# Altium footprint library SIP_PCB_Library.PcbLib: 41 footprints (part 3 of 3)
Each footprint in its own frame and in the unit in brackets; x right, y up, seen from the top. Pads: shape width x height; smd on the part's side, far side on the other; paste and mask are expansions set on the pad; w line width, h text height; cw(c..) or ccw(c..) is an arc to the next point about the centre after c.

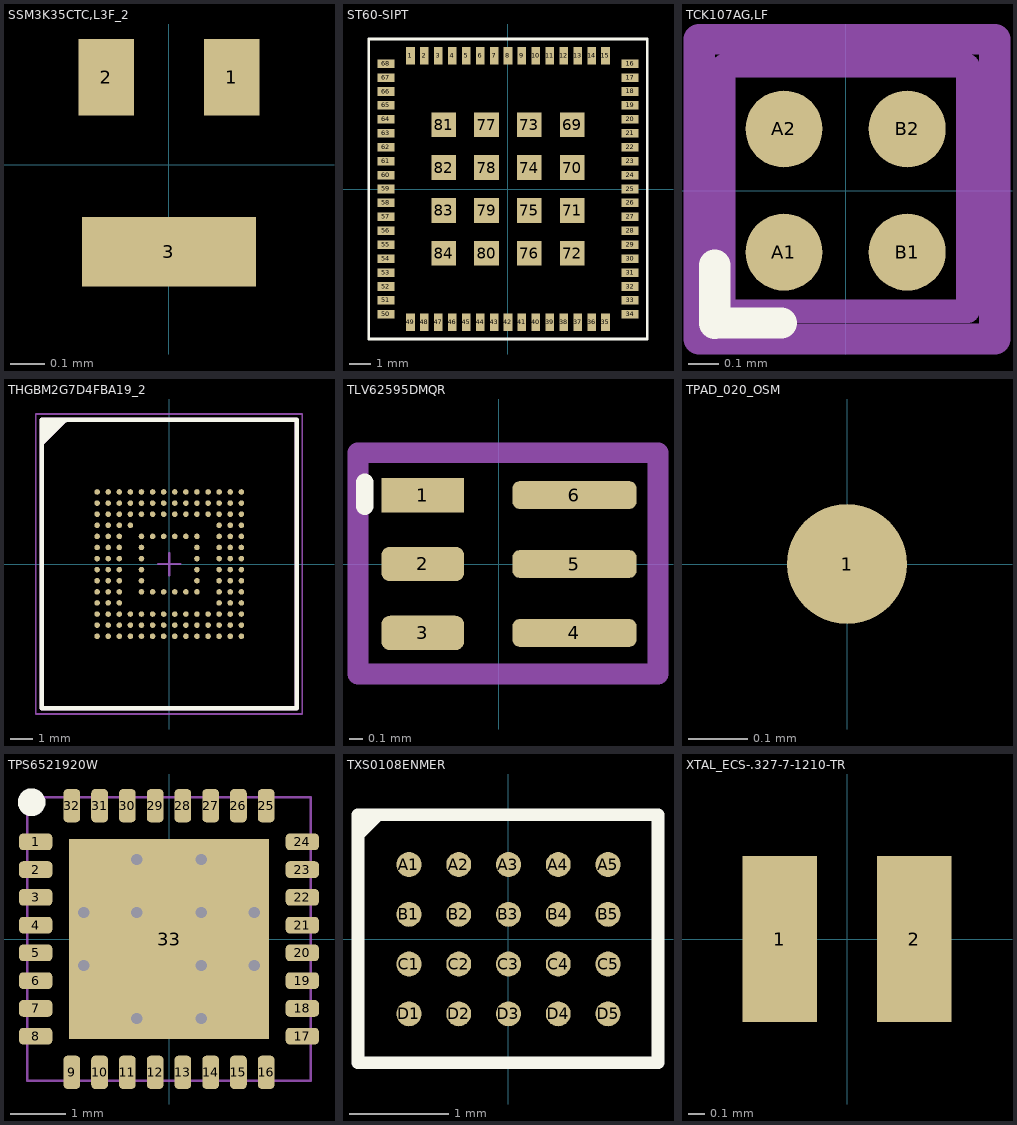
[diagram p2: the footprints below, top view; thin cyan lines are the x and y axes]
## SSM3K35CTC,L3F_2 [mm]
pads (3):
  rect 0.16x0.22 smd: 1(0.18,0.25) 2(-0.18,0.25)
  rect 0.5x0.2 smd: 3(0,-0.25)
3D body "CST3C_z90.stp": height 0.38, standoff 0, extent -0.3,-0.4 0.3,0.4

## ST60-SIPT [mm]
height 0.8
pads (84):
  rect 0.4x0.8 smd mask+0.051: 1(-4.55,6.219) 2(-3.9,6.219) 3(-3.25,6.219) 4(-2.6,6.219) 5(-1.95,6.219) 6(-1.3,6.219) 7(-0.65,6.219) 8(0,6.219) 9(0.65,6.219) 10(1.3,6.219) 11(1.95,6.219) 12(2.6,6.219) 13(3.25,6.219) 14(3.9,6.219) 15(4.55,6.219) 35(4.55,-6.219) 36(3.9,-6.219) 37(3.25,-6.219) 38(2.6,-6.219) 39(1.95,-6.219) 40(1.3,-6.219) 41(0.65,-6.219) 42(0,-6.219) 43(-0.65,-6.219) 44(-1.3,-6.219) 45(-1.95,-6.219) 46(-2.6,-6.219) 47(-3.25,-6.219) 48(-3.9,-6.219) 49(-4.55,-6.219)
  rect 0.8x0.4 smd mask+0.051: 16(5.694,5.85) 17(5.694,5.2) 18(5.694,4.55) 19(5.694,3.9) 20(5.694,3.25) 21(5.694,2.6) 22(5.694,1.95) 23(5.694,1.3) 24(5.694,0.65) 25(5.694,0) 26(5.694,-0.65) 27(5.694,-1.3) 28(5.694,-1.95) 29(5.694,-2.6) 30(5.694,-3.25) 31(5.694,-3.9) 32(5.694,-4.55) 33(5.694,-5.2) 34(5.694,-5.85) 50(-5.694,-5.85) 51(-5.694,-5.2) 52(-5.694,-4.55) 53(-5.694,-3.9) 54(-5.694,-3.25) 55(-5.694,-2.6) 56(-5.694,-1.95) 57(-5.694,-1.3) 58(-5.694,-0.65) 59(-5.694,0) 60(-5.694,0.65) 61(-5.694,1.3) 62(-5.694,1.95) 63(-5.694,2.6) 64(-5.694,3.25) 65(-5.694,3.9) 66(-5.694,4.55) 67(-5.694,5.2) 68(-5.694,5.85)
  rect 1.15x1.15 smd mask+0.051: 69(3,3) 70(3,1) 71(3,-1) 72(3,-3) 73(1,3) 74(1,1) 75(1,-1) 76(1,-3) 77(-1,3) 78(-1,1) 79(-1,-1) 80(-1,-3) 81(-3,3) 82(-3,1) 83(-3,-1) 84(-3,-3)
Top Overlay:
  lines w0.127: -6.5,-7 -6.5,7 6.5,7 6.5,-7 -6.5,-7
Top Courtyard:
  lines w0.025: 6.5,7 6.5,6.987 ; 6.5,6.987 -6.5,6.987 -6.5,-7 6.5,-7 6.5,6.987
3D body "453-00134.STEP": height 1.88, standoff -0.01, extent -6.5,-7 6.5,7

## TCK107AG,LF [mm]
pads (4):
  round 0.25 smd paste-0.03: A1(-0.2,-0.2) A2(-0.2,0.2) B1(0.2,-0.2) B2(0.2,0.2)
Top Overlay:
  lines w0.102: -0.424,-0.243 -0.424,-0.431 -0.209,-0.43
Mechanical 9:
  lines w0.076: -0.395,-0.392 0.396,-0.392 0.396,0.405 -0.395,0.405 -0.395,-0.371 -0.395,-0.392
Top Assembly:
  lines w0.102: -0.475,-0.482 0.484,-0.482 0.484,0.492 -0.475,0.492 -0.475,-0.482
  text "'.Designator'" at 6.86,2.581 h1.78
3D body "TCK107AG,LF.stp": height 0.59, standoff 0, extent -0.395,-0.395 0.395,0.395

## THGBM2G7D4FBA19_2 [mm] "BD584, BGA, 392-Leads, Body 16.0x12.0mm,  Pitch 0.50mm"
height 1.2
pads (153):
  round 0.25 smd: AA1(-3.25,-3.25) AA2(-2.75,-3.25) AA3(-2.25,-3.25) AA4(-1.75,-3.25) AA5(-1.25,-3.25) AA6(-0.75,-3.25) AA7(-0.25,-3.25) AA8(0.25,-3.25) AA9(0.75,-3.25) AA10(1.25,-3.25) AA11(1.75,-3.25) AA12(2.25,-3.25) AA13(2.75,-3.25) AA14(3.25,-3.25) H1(-3.25,3.25) H2(-2.75,3.25) H3(-2.25,3.25) H4(-1.75,3.25) H5(-1.25,3.25) H6(-0.75,3.25) H7(-0.25,3.25) H8(0.25,3.25) H9(0.75,3.25) H10(1.25,3.25) H11(1.75,3.25) H12(2.25,3.25) H13(2.75,3.25) H14(3.25,3.25) J1(-3.25,2.75) J2(-2.75,2.75) J3(-2.25,2.75) J4(-1.75,2.75) J5(-1.25,2.75) J6(-0.75,2.75) J7(-0.25,2.75) J8(0.25,2.75) J9(0.75,2.75) J10(1.25,2.75) J11(1.75,2.75) J12(2.25,2.75) J13(2.75,2.75) J14(3.25,2.75) K1(-3.25,2.25) K2(-2.75,2.25) K3(-2.25,2.25) K4(-1.75,2.25) K5(-1.25,2.25) K6(-0.75,2.25) K7(-0.25,2.25) K8(0.25,2.25) K9(0.75,2.25) K10(1.25,2.25) K11(1.75,2.25) K12(2.25,2.25) K13(2.75,2.25) K14(3.25,2.25) L1(-3.25,1.75) L2(-2.75,1.75) L3(-2.25,1.75) L4(-1.75,1.75) L12(2.25,1.75) L13(2.75,1.75) L14(3.25,1.75) M1(-3.25,1.25) M2(-2.75,1.25) M3(-2.25,1.25) M5(-1.25,1.25) M6(-0.75,1.25) M7(-0.25,1.25) M8(0.25,1.25) M9(0.75,1.25) M10(1.25,1.25) M12(2.25,1.25) M13(2.75,1.25) M14(3.25,1.25) N1(-3.25,0.75) N2(-2.75,0.75) N3(-2.25,0.75) N5(-1.25,0.75) N10(1.25,0.75) N12(2.25,0.75) N13(2.75,0.75) N14(3.25,0.75) P1(-3.25,0.25) P2(-2.75,0.25) P3(-2.25,0.25) P5(-1.25,0.25) P10(1.25,0.25) P12(2.25,0.25) P13(2.75,0.25) P14(3.25,0.25) R1(-3.25,-0.25) R2(-2.75,-0.25) R3(-2.25,-0.25) R5(-1.25,-0.25) R10(1.25,-0.25) R12(2.25,-0.25) R13(2.75,-0.25) R14(3.25,-0.25) T1(-3.25,-0.75) T2(-2.75,-0.75) T3(-2.25,-0.75) T5(-1.25,-0.75) T10(1.25,-0.75) T12(2.25,-0.75) T13(2.75,-0.75) T14(3.25,-0.75) U1(-3.25,-1.25) U2(-2.75,-1.25) U3(-2.25,-1.25) U5(-1.25,-1.25) U6(-0.75,-1.25) U7(-0.25,-1.25) U8(0.25,-1.25) U9(0.75,-1.25) U10(1.25,-1.25) U12(2.25,-1.25) U13(2.75,-1.25) U14(3.25,-1.25) V1(-3.25,-1.75) V2(-2.75,-1.75) V3(-2.25,-1.75) V12(2.25,-1.75) V13(2.75,-1.75) V14(3.25,-1.75) W1(-3.25,-2.25) W2(-2.75,-2.25) W3(-2.25,-2.25) W4(-1.75,-2.25) W5(-1.25,-2.25) W6(-0.75,-2.25) W7(-0.25,-2.25) W8(0.25,-2.25) W9(0.75,-2.25) W10(1.25,-2.25) W11(1.75,-2.25) W12(2.25,-2.25) W13(2.75,-2.25) W14(3.25,-2.25) Y1(-3.25,-2.75) Y2(-2.75,-2.75) Y3(-2.25,-2.75) Y4(-1.75,-2.75) Y5(-1.25,-2.75) Y6(-0.75,-2.75) Y7(-0.25,-2.75) Y8(0.25,-2.75) Y9(0.75,-2.75) Y10(1.25,-2.75) Y11(1.75,-2.75) Y12(2.25,-2.75) Y13(2.75,-2.75) Y14(3.25,-2.75)
Top Overlay:
  circle w0.25: c-5.435,6.17 r0.125
  region: -4.77,6.49 -5.77,5.49 -5.77,6.49
  lines w0.2: -5.715,5.46 -4.715,6.46 ; 5.75,-6.5 5.75,6.5 ; 5.75,-6.5 -5.75,-6.5 -5.75,6.5 5.75,6.5
Mechanical 8:
  text "'.Designator'" at -2.957,-0.361 h1.78
Mechanical 9:
  lines w0.076: -6.02,-6.754 5.999,-6.754 5.999,6.764 -6.02,6.764 -6.02,-6.754
  lines w0.1: -0.5,0 0.5,0 ; 0,-0.5 0,0.5
Top Assembly:
  region: -4.77,6.49 -5.77,5.49 -5.77,6.49
  lines w0.2: -5.715,5.46 -4.715,6.46 ; 5.75,-6.5 5.75,6.5 ; 5.75,-6.5 -5.75,-6.5 -5.75,6.5 5.75,6.5
3D body "EMMC16G-TB29-70H01.stp": height 0.8, standoff 0, extent -5.75,-6.5 5.75,6.5

## TLV62595DMQR [mm]
pads (6):
  rect 0.6x0.25 smd: 1(-0.55,0.5)
  rrect50% 0.6x0.25 smd: 2(-0.55,0) 3(-0.55,-0.5)
  rrect50% 0.9x0.2 smd: 4(0.55,-0.5) 5(0.55,0) 6(0.55,0.5)
Top Overlay:
  lines w0.127: -0.969,0.418 -0.969,0.594
Top Courtyard:
  lines w0.15: -1.019,-0.798 -1.019,0.807 1.155,0.807 1.155,-0.798 -1.019,-0.798
3D body "TLV62595DMQR.STEP": height 1, standoff 0, extent -0.75,-0.75 0.75,0.75

## TPAD_020_OSM [mil]
pads (1):
  round 8 smd paste-15.75: 1(0,0)
Mechanical 1:

## TPS6521920W [mm]
pads (33):
  rrect50% 0.6x0.3 smd: 1(-2.4,1.75) 2(-2.4,1.25) 3(-2.4,0.75) 4(-2.4,0.25) 5(-2.4,-0.25) 6(-2.4,-0.75) 7(-2.4,-1.25) 8(-2.4,-1.75) 17(2.4,-1.75) 18(2.4,-1.25) 19(2.4,-0.75) 20(2.4,-0.25) 21(2.4,0.25) 22(2.4,0.75) 23(2.4,1.25) 24(2.4,1.75)
  rrect50% 0.3x0.6 smd: 9(-1.75,-2.4) 10(-1.25,-2.4) 11(-0.75,-2.4) 12(-0.25,-2.4) 13(0.25,-2.4) 14(0.75,-2.4) 15(1.25,-2.4) 16(1.75,-2.4) 25(1.75,2.4) 26(1.25,2.4) 27(0.75,2.4) 28(0.25,2.4) 29(-0.25,2.4) 30(-0.75,2.4) 31(-1.25,2.4) 32(-1.75,2.4)
  rect 3.6x3.6 smd: 33(0,0)
via -1.533,-0.477 diameter 0.457 hole 0.203
via -1.533,0.477 diameter 0.457 hole 0.203
via -0.58,0.477 diameter 0.457 hole 0.203
via 0.58,-1.43 diameter 0.457 hole 0.203
via -0.58,-1.43 diameter 0.457 hole 0.203
via 0.58,-0.477 diameter 0.457 hole 0.203
via 1.533,-0.477 diameter 0.457 hole 0.203
via -0.58,1.43 diameter 0.457 hole 0.203
via 0.58,1.43 diameter 0.457 hole 0.203
via 0.58,0.477 diameter 0.457 hole 0.203
via 1.533,0.477 diameter 0.457 hole 0.203
Top Overlay:
  circle w0.25: c-2.472,2.462 r0.125
Bottom Assembly:
  lines w0.05: -2.553,-2.553 2.553,-2.553 2.553,2.553 -2.553,2.553 -2.553,-2.553
3D body "VQFN32_RHB_TEX.step": height 0.99, standoff 0, extent -2.553,-2.553 2.553,2.553

## TXS0108ENMER [mm]
height 0.625
pads (20):
  round 0.25 smd mask+0.03: A1(-1,0.75) A2(-0.5,0.75) A3(0,0.75) A4(0.5,0.75) A5(1,0.75) B1(-1,0.25) B2(-0.5,0.25) B3(0,0.25) B4(0.5,0.25) B5(1,0.25) C1(-1,-0.25) C2(-0.5,-0.25) C3(0,-0.25) C4(0.5,-0.25) C5(1,-0.25) D1(-1,-0.75) D2(-0.5,-0.75) D3(0,-0.75) D4(0.5,-0.75) D5(1,-0.75)
Top Overlay:
  lines w0.127: -1.5,1.06 -1.31,1.25 -0.768,1.25 ; -1.512,-1.241 -1.512,1.25 1.502,1.25 1.502,-1.241 -1.512,-1.241
Top Assembly:
  lines w0.076: -1.512,-1.246 -1.512,1.25 1.502,1.25 1.502,-1.246 -1.512,-1.246
  text "'.Designator'" at -2.087,-0.241 h0.89
3D body "NME0020A.stp": height 1, standoff 0, extent -1.5,-1.25 1.5,1.25

## XTAL_ECS-.327-7-1210-TR [mil]
pads (2):
  rect 18x40 smd: 1(-16.24,0) 2(16.24,0)
3D body "ECS-.327-7-1210-TR.step": height 13.78, standoff 0, extent -23.62,-19.68 23.62,19.68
